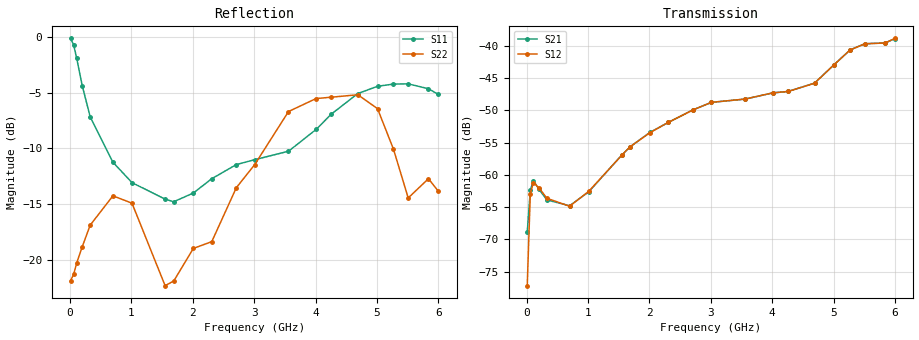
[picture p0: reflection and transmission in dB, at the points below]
!Agilent Technologies,N5230A,MY45001650,A.07.50.48
!Agilent N5230A: A.07.50.48
!Date: Saturday, July 08, 2017 15:44:15
!Correction: S11(Full 2 Port(1,2))
!S21(Full 2 Port(1,2))
!S12(Full 2 Port(1,2))
!S22(Full 2 Port(1,2))
!S2P File: Measurements: S11, S21, S12, S22:
# Hz S  dB  R 50
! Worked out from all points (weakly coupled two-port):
!   600 points, 10 MHz to 6 GHz, reference 50 ohm
!   highest |S21| = -38.88 dB at 6 GHz (marker M1); lowest = -68.9 dB at 10 MHz (marker M2)
!   lowest |S11| = -14.8 dB at 1.69 GHz (marker M3), VSWR 1.44, Z = 34.6 + j1.18 ohm
!   |S11| at or under -10 dB: 553.7 MHz to 3.663 GHz (3.11 GHz wide, 147 % of centre)
!   |S22| runs from -22.7 to -5.2 dB; largest |S21 - S12| = 0.00023
!   S11 on the Smith chart (normalised r, x): 10 MHz: 3, -20; 110 MHz: 0.52, -1.89; 330 MHz: 0.55, -0.56; 2.71 GHz: 0.58, +0.09; 4.26 GHz: 1.37, +1.12; 6 GHz: 2.60, -1.42
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1e7  -0.11 -5.7  -68.87 72.8  -77.20 82.5  -21.89 -7.9
6e7  -0.70 -31.6  -62.41 25.7  -62.91 24.7  -21.33 -22.4
1.1e8  -1.91 -53.1  -60.90 -5.7  -61.21 -6.7  -20.30 -38.0
2e8  -4.37 -81.2  -62.24 -38.4  -62.01 -39.0  -18.85 -62.0
3.3e8  -7.18 -109.0  -63.90 -68.3  -63.64 -66.7  -16.90 -88.5
7e8  -11.25 -153.8  -64.80 -135.2  -64.88 -135.3  -14.27 -136.4
1.01e9  -13.08 -172.4  -62.66 170.8  -62.58 170.9  -14.93 -166.3
1.55e9  -14.57 174.3  -56.95 95.3  -56.96 95.2  -22.35 171.5
1.69e9  -14.80 174.8  -55.63 77.5  -55.62 77.5  -21.93 -176.0
2.01e9  -14.02 176.9  -53.41 39.6  -53.46 39.7  -19.00 174.0
2.31e9  -12.73 173.8  -51.87 9.7  -51.86 9.6  -18.39 166.8
2.71e9  -11.46 164.7  -49.93 -29.7  -49.94 -29.5  -13.54 164.5
3.01e9  -11.02 149.6  -48.77 -60.9  -48.76 -60.7  -11.46 154.4
3.56e9  -10.26 107.0  -48.26 -112.7  -48.25 -112.6  -6.69 143.1
4.01e9  -8.30 64.1  -47.30 -151.3  -47.29 -151.3  -5.52 117.3
4.26e9  -6.91 46.2  -47.07 -173.2  -47.08 -173.1  -5.40 103.8
4.69e9  -5.07 23.9  -45.78 158.3  -45.80 158.4  -5.18 68.7
5.01e9  -4.42 12.9  -42.91 132.5  -42.91 132.6  -6.43 32.6
5.27e9  -4.22 5.6  -40.63 100.7  -40.64 100.8  -10.07 6.0
5.51e9  -4.20 -1.8  -39.67 67.9  -39.68 68.1  -14.46 12.4
5.84e9  -4.64 -13.1  -39.55 33.4  -39.56 33.5  -12.73 8.4
6e9  -5.15 -20.1  -38.88 20.7  -38.84 20.6  -13.85 -5.2
